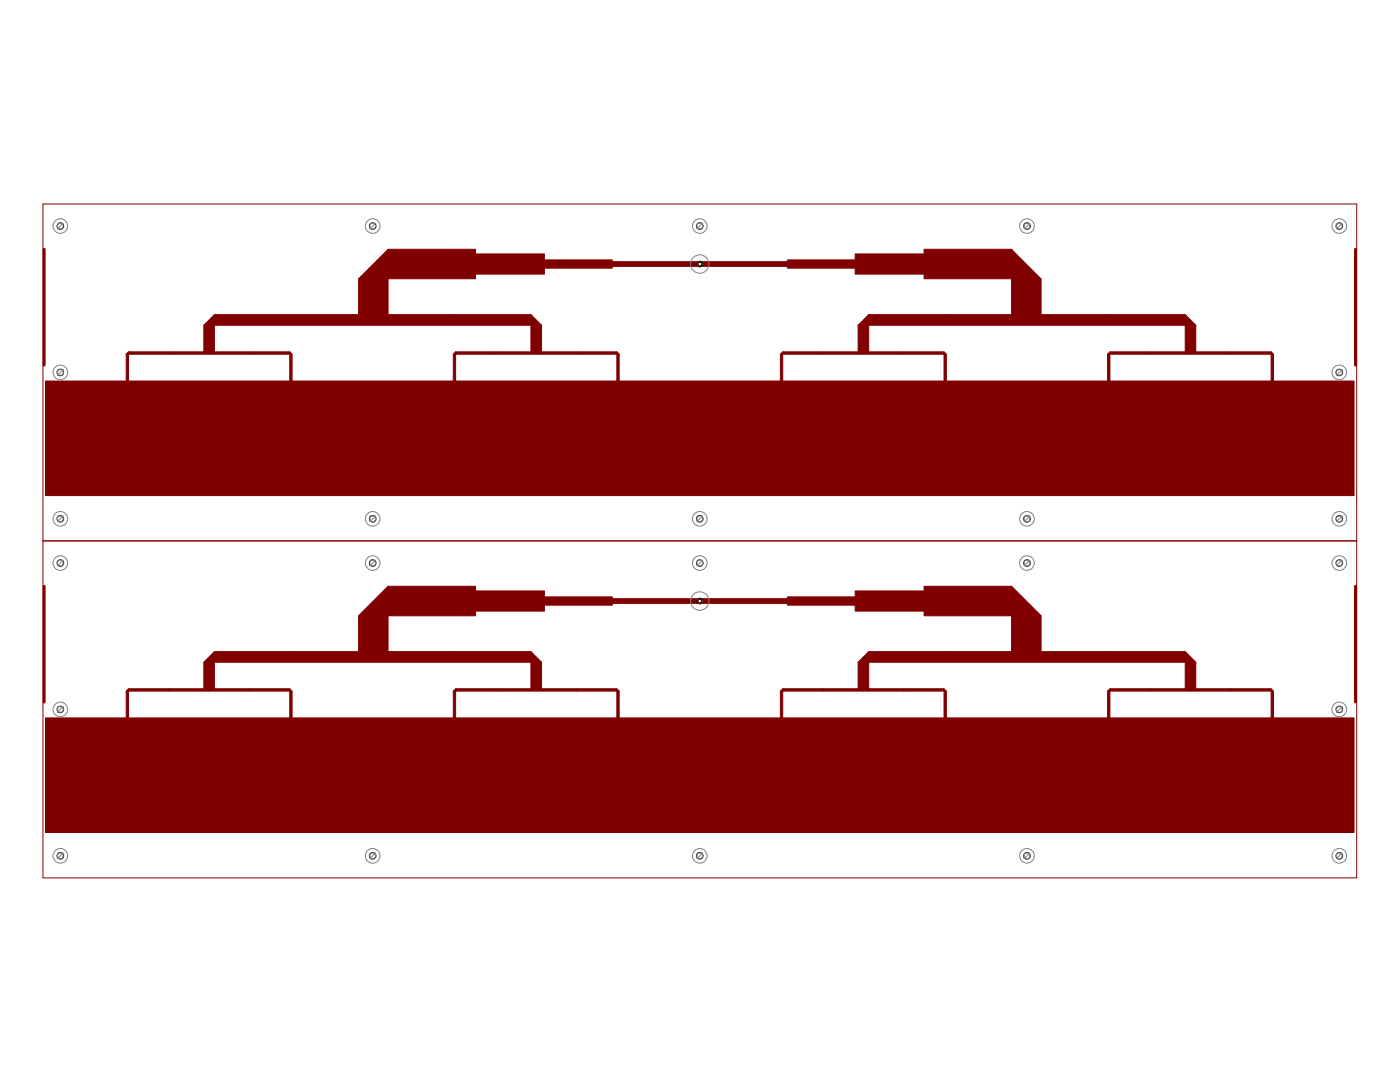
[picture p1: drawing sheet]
<svg xmlns="http://www.w3.org/2000/svg" width="279mm" height="216mm" viewBox="0 0 279 216" stroke-linecap="round" stroke-linejoin="round" font-family="sans-serif">
<circle cx="139.7" cy="119.9" r=".55" fill="#008000" stroke="#008000" stroke-width=".2"/>
<circle cx="139.7" cy="119.9" r=".36" fill="#fff" stroke="#000" stroke-width=".2"/>
<circle cx="139.7" cy="52.7" r=".55" fill="#008000" stroke="#008000" stroke-width=".2"/>
<circle cx="139.7" cy="52.7" r=".36" fill="#fff" stroke="#000" stroke-width=".2"/>
<g fill="#800000" stroke="#800000" stroke-width=".2">
<path d="M122.2 119.5h17.5v.9h-17.5z"/>
<path d="M139.7 119.5h17.4v.9h-17.4z"/>
<path d="M108.6 119.1h13.6v1.7h-13.6z"/>
<path d="M157.1 119.1h13.6v1.7h-13.6z"/>
<path d="M94.9 117.9h13.7v4h-13.7z"/>
<path d="M170.7 117.9h13.7v4h-13.7z"/>
<path d="M77.4 117h17.5v5.9h-17.5z"/>
<path d="M184.4 117h17.5v5.9h-17.5z"/>
<path d="M71.6 122.8l5.8-5.8 3 2.9-5.9 5.9z"/>
<path d="M201.9 117l5.8 5.8-2.9 3-5.8-5.9z"/>
<path d="M71.6 122.9h5.8v8.2h-5.8z"/>
<path d="M201.9 122.9h5.9v8.2h-5.9z"/>
<path d="M58.6 130h15.8v2.1h-15.8z"/>
<path d="M74.4 130h15.8v2.1h-15.8z"/>
<path d="M42.8 130h15.8v2.1h-15.8z"/>
<path d="M90.2 130h15.8v2.1h-15.8z"/>
<path d="M40.7 132.1l2.1-2.1 1.1 1.1-2.2 2.1z"/>
<path d="M236.5 130l2.2 2.1-1.1 1.1-2.1-2.1z"/>
<path d="M40.7 132.1h2.1v5.6h-2.1z"/>
<path d="M106 132.1h2.1v5.6h-2.1z"/>
<path d="M189.2 130h15.8v2.1h-15.8z"/>
<path d="M205 130h15.7v2.1h-15.7z"/>
<path d="M173.4 130h15.8v2.1h-15.8z"/>
<path d="M220.7 130h15.8v2.1h-15.8z"/>
<path d="M171.3 132.1l2.1-2.1 1 1.1-2.1 2.1z"/>
<path d="M104.9 131.1l1.1-1.1 2.1 2.1-1.1 1.1z"/>
<path d="M171.3 132.1h2.1v5.6h-2.1z"/>
<path d="M236.5 132.1h2.2v5.6h-2.2z"/>
<path d="M33.7 137.4h8v.5h-8z"/>
<path d="M41.7 137.4h8.1v.5h-8.1z"/>
<path d="M25.7 137.4h8v.5h-8z"/>
<path d="M49.8 137.4h8v.5h-8z"/>
<path d="M25.2 137.9l.5-.5 .2 .3-.5 .5z"/>
<path d="M253.4 137.7l.3-.3 .4 .5-.2 .3z"/>
<path d="M25.2 137.9h.5v5.4h-.5z"/>
<path d="M57.8 137.9h.5v5.4h-.5z"/>
<path d="M99 137.4h8v.5h-8z"/>
<path d="M107 137.4h8.1v.5h-8.1z"/>
<path d="M90.9 137.4h8.1v.5h-8.1z"/>
<path d="M115.1 137.4h8v.5h-8z"/>
<path d="M90.9 137.4l.3 .3-.5 .5-.2-.3z"/>
<path d="M188.4 137.4l.5 .5-.3 .3-.5-.5z"/>
<path d="M90.5 137.9h.4v5.4h-.4z"/>
<path d="M123.1 137.9h.5v5.4h-.5z"/>
<path d="M164.3 137.4h8v.5h-8z"/>
<path d="M172.3 137.4h8.1v.5h-8.1z"/>
<path d="M156.2 137.4h8.1v.5h-8.1z"/>
<path d="M180.3 137.4h8.1v.5h-8.1z"/>
<path d="M155.7 137.9l.5-.5 .3 .3-.5 .5z"/>
<path d="M122.9 137.7l.2-.3 .5 .5-.3 .3z"/>
<path d="M155.7 137.9h.5v5.4h-.5z"/>
<path d="M188.4 137.9h.5v5.4h-.5z"/>
<path d="M229.5 137.4h8.1v.5h-8.1z"/>
<path d="M237.6 137.4h8v.5h-8z"/>
<path d="M221.5 137.4h8v.5h-8z"/>
<path d="M245.6 137.4h8.1v.5h-8.1z"/>
<path d="M221 137.9l.5-.5 .3 .3-.5 .5z"/>
<path d="M57.6 137.7l.2-.3 .5 .5-.2 .3z"/>
<path d="M221 137.9h.5v5.4h-.5z"/>
<path d="M253.7 137.9h.4v5.4h-.4z"/>
<path d="M9.1 143.3h261.1v22.8h-261.1z"/>
<path d="M122.2 52.2h17.5v.9h-17.5z"/>
<path d="M139.7 52.2h17.4v.9h-17.4z"/>
<path d="M108.6 51.9h13.6v1.6h-13.6z"/>
<path d="M157.1 51.9h13.6v1.6h-13.6z"/>
<path d="M94.9 50.7h13.7v4h-13.7z"/>
<path d="M170.7 50.7h13.7v4h-13.7z"/>
<path d="M77.4 49.7h17.5v5.9h-17.5z"/>
<path d="M184.4 49.7h17.5v5.9h-17.5z"/>
<path d="M71.6 55.6l5.8-5.8 3 2.9-5.9 5.8z"/>
<path d="M199 52.7l2.9-2.9 5.8 5.8-2.9 2.9z"/>
<path d="M71.6 55.6h5.8v8.2h-5.8z"/>
<path d="M201.9 55.6h5.9v8.2h-5.9z"/>
<path d="M58.6 62.8h15.8v2.1h-15.8z"/>
<path d="M74.4 62.8h15.8v2.1h-15.8z"/>
<path d="M42.8 62.8h15.8v2.1h-15.8z"/>
<path d="M90.2 62.8h15.8v2.1h-15.8z"/>
<path d="M40.7 64.9l2.1-2.1 1.1 1-2.2 2.2z"/>
<path d="M235.5 63.8l1-1 2.2 2.1-1.1 1.1z"/>
<path d="M40.7 64.9h2.1v5.5h-2.1z"/>
<path d="M106 64.9h2.1v5.5h-2.1z"/>
<path d="M189.2 62.8h15.8v2.1h-15.8z"/>
<path d="M205 62.8h15.7v2.1h-15.7z"/>
<path d="M173.4 62.8h15.8v2.1h-15.8z"/>
<path d="M220.7 62.8h15.8v2.1h-15.8z"/>
<path d="M171.3 64.9l2.1-2.1 1 1-2.1 2.2z"/>
<path d="M104.9 63.8l1.1-1 2.1 2.1-1.1 1.1z"/>
<path d="M171.3 64.9h2.1v5.5h-2.1z"/>
<path d="M236.5 64.9h2.2v5.5h-2.2z"/>
<path d="M33.7 70.2h8v.5h-8z"/>
<path d="M41.7 70.2h8.1v.5h-8.1z"/>
<path d="M25.7 70.2h8v.5h-8z"/>
<path d="M49.8 70.2h8v.5h-8z"/>
<path d="M25.2 70.7l.5-.5 .2 .2-.5 .5z"/>
<path d="M253.4 70.4l.3-.2 .4 .5-.2 .2z"/>
<path d="M25.2 70.7h.5v5.3h-.5z"/>
<path d="M57.8 70.7h.5v5.3h-.5z"/>
<path d="M99 70.2h8v.5h-8z"/>
<path d="M107 70.2h8.1v.5h-8.1z"/>
<path d="M90.9 70.2h8.1v.5h-8.1z"/>
<path d="M115.1 70.2h8v.5h-8z"/>
<path d="M90.9 70.2l.3 .2-.5 .5-.2-.2z"/>
<path d="M188.4 70.2l.5 .5-.3 .2-.5-.5z"/>
<path d="M90.5 70.7h.4v5.3h-.4z"/>
<path d="M123.1 70.7h.5v5.3h-.5z"/>
<path d="M164.3 70.2h8v.5h-8z"/>
<path d="M172.3 70.2h8.1v.5h-8.1z"/>
<path d="M156.2 70.2h8.1v.5h-8.1z"/>
<path d="M180.3 70.2h8.1v.5h-8.1z"/>
<path d="M155.7 70.7l.5-.5 .3 .2-.5 .5z"/>
<path d="M123.1 70.2l.5 .5-.3 .2-.4-.5z"/>
<path d="M155.7 70.7h.5v5.3h-.5z"/>
<path d="M188.4 70.7h.5v5.3h-.5z"/>
<path d="M229.5 70.2h8.1v.5h-8.1z"/>
<path d="M237.6 70.2h8v.5h-8z"/>
<path d="M221.5 70.2h8v.5h-8z"/>
<path d="M245.6 70.2h8.1v.5h-8.1z"/>
<path d="M221 70.7l.5-.5 .3 .2-.5 .5z"/>
<path d="M57.6 70.4l.2-.2 .5 .5-.2 .2z"/>
<path d="M221 70.7h.5v5.3h-.5z"/>
<path d="M253.7 70.7h.4v5.3h-.4z"/>
<path d="M9.1 76h261.1v22.9h-261.1z"/>
</g>
<g fill="#800000" stroke="#800000" stroke-width=".59">
<path d="M270.5 117v23.1z"/>
<path d="M8.8 117v23.1z"/>
<path d="M270.5 49.7v23.2z"/>
<path d="M8.8 49.7v23.2z"/>
</g>
<g fill="#800000" stroke="#800000" stroke-width=".2">
<path d="M8.6 107.9h262.2z"/>
<path d="M8.6 107.9v67.3z"/>
<path d="M8.6 175.2h262.2z"/>
<path d="M270.8 107.9v67.3z"/>
<path d="M8.6 40.7h262.2z"/>
<path d="M8.6 40.7v67.2z"/>
<path d="M270.8 40.7v67.2z"/>
</g>
<circle cx="139.7" cy="119.9" r=".55" fill="#008000" stroke="#008000" stroke-width=".2"/>
<circle cx="139.7" cy="119.9" r=".36" fill="#fff" stroke="#000" stroke-width=".2"/>
<circle cx="139.7" cy="52.7" r=".55" fill="#008000" stroke="#008000" stroke-width=".2"/>
<circle cx="139.7" cy="52.7" r=".36" fill="#fff" stroke="#000" stroke-width=".2"/>
<g fill="none" stroke="#808080" stroke-width=".2">
<circle cx="12" cy="45.1" r="1.46"/>
<circle cx="12" cy="45.1" r=".57"/>
<circle cx="74.4" cy="45.1" r="1.46"/>
<circle cx="74.4" cy="45.1" r=".57"/>
<circle cx="139.7" cy="52.7" r="1.84"/>
<circle cx="139.7" cy="45.1" r="1.46"/>
<circle cx="139.7" cy="45.1" r=".57"/>
<circle cx="205" cy="45.1" r="1.46"/>
<circle cx="205" cy="45.1" r=".57"/>
<circle cx="267.3" cy="45.1" r="1.46"/>
<circle cx="267.3" cy="45.1" r=".57"/>
<circle cx="12" cy="74.3" r="1.46"/>
<circle cx="12" cy="74.3" r=".57"/>
<circle cx="267.3" cy="74.3" r="1.46"/>
<circle cx="267.3" cy="74.3" r=".57"/>
<circle cx="12" cy="103.5" r="1.46"/>
<circle cx="12" cy="112.4" r="1.46"/>
<circle cx="12" cy="112.4" r=".57"/>
<circle cx="12" cy="103.5" r=".57"/>
<circle cx="74.4" cy="112.4" r="1.46"/>
<circle cx="74.4" cy="103.5" r="1.46"/>
<circle cx="74.4" cy="103.5" r=".57"/>
<circle cx="74.4" cy="112.4" r=".57"/>
<circle cx="139.7" cy="119.9" r="1.84"/>
<circle cx="139.7" cy="103.5" r="1.46"/>
<circle cx="139.7" cy="112.4" r="1.46"/>
<circle cx="139.7" cy="103.5" r=".57"/>
<circle cx="139.7" cy="112.4" r=".57"/>
<circle cx="205" cy="103.5" r="1.46"/>
<circle cx="205" cy="112.4" r="1.46"/>
<circle cx="205" cy="112.4" r=".57"/>
<circle cx="205" cy="103.5" r=".57"/>
<circle cx="267.3" cy="103.5" r="1.46"/>
<circle cx="267.3" cy="112.4" r="1.46"/>
<circle cx="267.3" cy="103.5" r=".57"/>
<circle cx="267.3" cy="112.4" r=".57"/>
<circle cx="12" cy="141.6" r="1.46"/>
<circle cx="12" cy="141.6" r=".57"/>
<circle cx="267.3" cy="141.6" r="1.46"/>
<circle cx="267.3" cy="141.6" r=".57"/>
<circle cx="12" cy="170.8" r="1.46"/>
<circle cx="12" cy="170.8" r=".57"/>
<circle cx="74.4" cy="170.8" r="1.46"/>
<circle cx="74.4" cy="170.8" r=".57"/>
<circle cx="139.7" cy="170.8" r="1.46"/>
<circle cx="139.7" cy="170.8" r=".57"/>
<circle cx="205" cy="170.8" r="1.46"/>
<circle cx="205" cy="170.8" r=".57"/>
<circle cx="267.3" cy="170.8" r="1.46"/>
<circle cx="267.3" cy="170.8" r=".57"/>
</g>
<g fill="none" stroke="#000" stroke-width=".2">
<circle cx="12" cy="45.1" r=".66"/>
<circle cx="74.4" cy="45.1" r=".66"/>
<circle cx="139.7" cy="45.1" r=".66"/>
<circle cx="205" cy="45.1" r=".66"/>
<circle cx="267.3" cy="45.1" r=".66"/>
<circle cx="12" cy="74.3" r=".66"/>
<circle cx="267.3" cy="74.3" r=".66"/>
<circle cx="12" cy="103.5" r=".66"/>
<circle cx="12" cy="112.4" r=".66"/>
<circle cx="74.4" cy="103.5" r=".66"/>
<circle cx="74.4" cy="112.4" r=".66"/>
<circle cx="139.7" cy="112.4" r=".66"/>
<circle cx="139.7" cy="103.5" r=".66"/>
<circle cx="205" cy="103.5" r=".66"/>
<circle cx="205" cy="112.4" r=".66"/>
<circle cx="267.3" cy="112.4" r=".66"/>
<circle cx="267.3" cy="103.5" r=".66"/>
<circle cx="12" cy="141.6" r=".66"/>
<circle cx="267.3" cy="141.6" r=".66"/>
<circle cx="12" cy="170.8" r=".66"/>
<circle cx="74.4" cy="170.8" r=".66"/>
<circle cx="139.7" cy="170.8" r=".66"/>
<circle cx="205" cy="170.8" r=".66"/>
<circle cx="267.3" cy="170.8" r=".66"/>
</g>
<g fill="#808080" stroke="#808080" stroke-width=".2">
<path d="M11.5 112.9l1.1-1.1z"/>
<path d="M11.5 142.1l1.1-1.1z"/>
<path d="M11.5 171.3l1.1-1.1z"/>
<path d="M73.8 112.9l1.2-1.1z"/>
<path d="M73.8 171.3l1.2-1.1z"/>
<path d="M139.1 112.9l1.1-1.1z"/>
<path d="M139.1 171.3l1.1-1.1z"/>
<path d="M204.4 112.9l1.1-1.1z"/>
<path d="M204.4 171.3l1.1-1.1z"/>
<path d="M266.7 112.9l1.2-1.1z"/>
<path d="M266.7 142.1l1.2-1.1z"/>
<path d="M266.7 171.3l1.2-1.1z"/>
<path d="M12.6 44.5l-1.1 1.2z"/>
<path d="M12.6 73.7l-1.1 1.2z"/>
<path d="M12.6 102.9l-1.1 1.2z"/>
<path d="M73.8 45.7l1.2-1.2z"/>
<path d="M73.8 104.1l1.2-1.2z"/>
<path d="M140.2 44.5l-1.1 1.2z"/>
<path d="M140.2 102.9l-1.1 1.2z"/>
<path d="M204.4 45.7l1.1-1.2z"/>
<path d="M204.4 104.1l1.1-1.2z"/>
<path d="M266.7 45.7l1.2-1.2z"/>
<path d="M266.7 74.9l1.2-1.2z"/>
<path d="M266.7 104.1l1.2-1.2z"/>
</g>
</svg>
